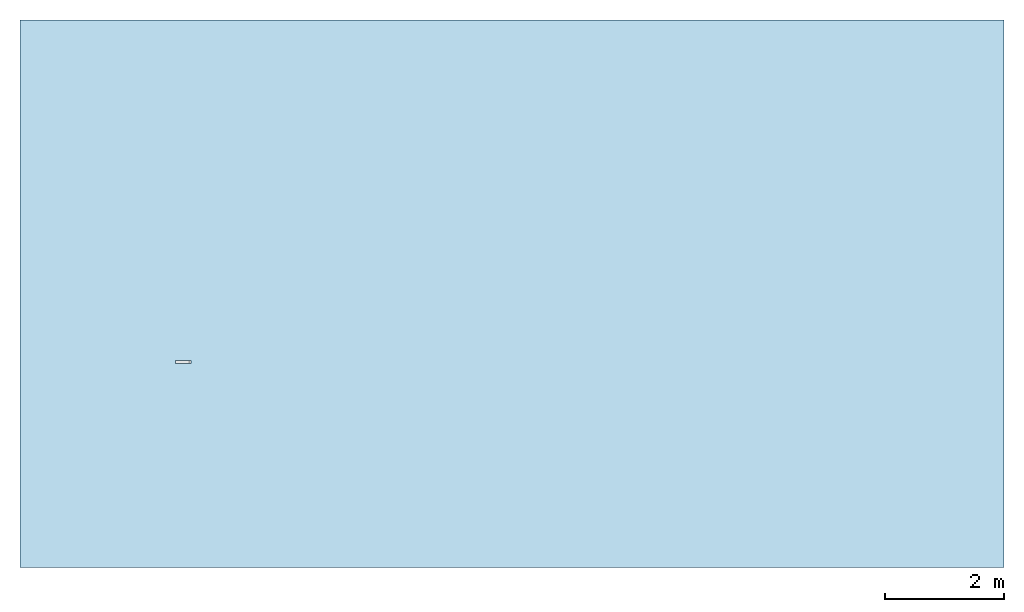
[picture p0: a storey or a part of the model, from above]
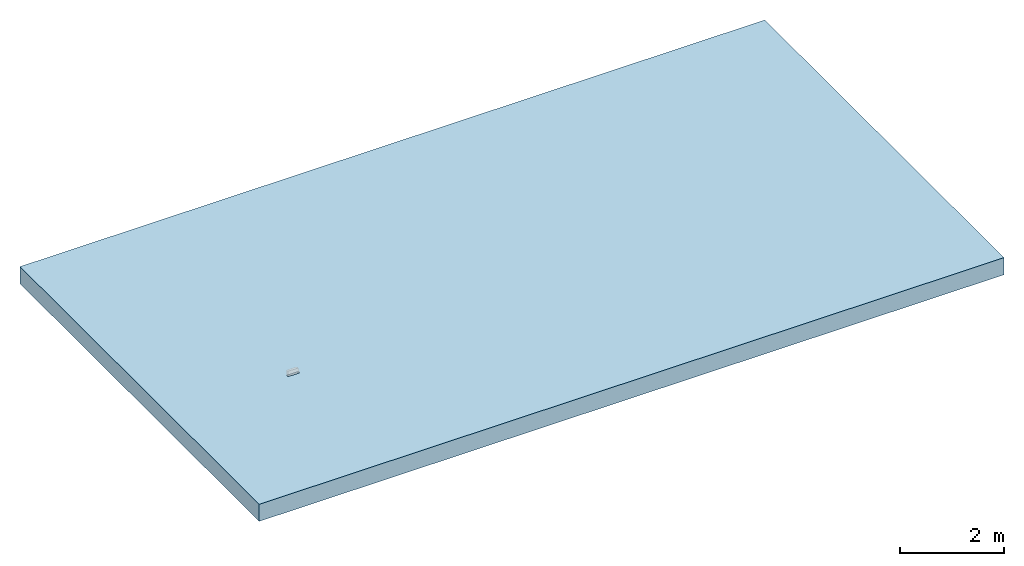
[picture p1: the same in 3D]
Properties of the parts of a building model (IFC2X3)

# File
Description: ViewDefinition [CoordinationView]
File name: T0134 - Closing end cap.ifc
Time: 2013-09-04T09:03:45
Written by: Autodesk Revit 2013
Made in: 20120221_2030(x64)

# IfcProject, Project Number
LongName: Project Name; Phase: Project Status

# IfcSite, Default
RefLatitude: 42, 21, 30, 344238; RefLongitude: -71, -3, -35, -194702; RefElevation: 0 mm

# IfcBuilding
Pset_BuildingCommon - NumberOfStoreys: 1
Other - Project Number: Project Number; Project Name: Project Name; Project Issue Date: Issue Date; Project Address: ## Street City, State Zip; Client Name: Owner; Project Status: Project Status

# IfcBuildingStorey, Level 1
LongName: Level 1; Elevation: 0 mm
Constraints - Elevation Base: 0; Elevation: 0 mm
Graphics - Line Pattern: Center; Line Weight: 1; Symbol at End 2 Default: yes; Color: 0; Symbol at End 1 Default: no; Symbol: M_Level Head - Circle: M_Level Head - Circle
Identity Data - Name: Level 1; Structural: no; Building Story: yes
Dimensions - Computation Height: 0 mm

# IfcBuildingElementProxy: T0134 - Closing end cap, Civil-Drainage-Channel-ACO-KerbDrain-KD200:T0134 - Closing end cap:T0134 - Closing end cap:308203
In: Level 1
Material: ACO Polymer Concrete.
Phasing - Phase Created: New Construction
Constraints - Level: Level: Level 1; Moves With Nearby Elements: no
Dimensions - Volume: 2985972 mm3; Void Depth.: -110 mm; Void length: 50 mm
Pset_BuildingElementProxyCommon - Reference: T0134 - Closing end cap
Identity Data - Assembly Description: Rain Water Drainage; Maintenance guidelines: http://www.aco.co.uk/download.php?id=120; e-mail Technical: technical@aco.co.uk; Assembly Code: D2040; URL: www.aco.co.uk; Type Comments: ACO KerbDrain KD200 half batter closing end cap; OmniClass Title: Rainwater Removal; Price: POA - contact ACO; Installation guidelines: http://www.aco.co.uk/download.php?id=120; Cost: 0; Manufacturer: ACO Technologies plc - ACO Water Management Division; Model: ACO KerbDrain KD200; Product Page URL: http://www.aco.co.uk/product_detail.php?id=3; Fax: +44 (0)1462 815895; Address: ACO Business Park, Hitchin Road, Shefford, Bedfordshire, United Kingdom SG17 5TE; OmniClass Number: 23.70.50.24; Product brochure: http://www.aco.co.uk/download.php?id=120; Model Description: Combined kerb and drainage system; Product Code: T0134; e-mail Sales: customersupport@aco.co.uk; Telephone: +44 (0)1462 816666
Data - Drainage Slot Width: N/A; Drainage Slot Intake area: N/A; Invert Depth: N/A; Installation - Concrete Grade: N/A; ACO Hydraulic Design Software: N/A; Concrete Surround Volume - Load Class A 15 - D 400 - Concrete Pavement: N/A; Product Standard: N/A; Product Dimensions: 50mm x 260mm x 235mm (LxWxH); Channel C.S.A: N/A; Load Class: N/A; Hydraulic Performance: N/A; Product Weight: 6.5 Kg
Construction - Channelunit_220: no; Blindunit_220: no; Access Cover: no; Blindunit_235: no; Channelunit_235: no; Closing end cap: yes; Accessunit_220: no; Accessunit_235: no
General - TagNumber: 0.000000; SerialNumber: 0.000000
Green Building Properties - Access Cover/Frame Recyclable: N/A; End Cap Recycled Material Content: 20% minimum; Access Cover/Frame Recycled Material Content: N/A; Channel Recycled Material Content: N/A; End Cap Recyclable: Fully recyclable; Channel Recyclable: N/A
Other - Revision: 1; CreatedBy: www.aco.co.uk
Materials and Finishes - Access Cover/Frame Colour: N/A; End Cap Colour: Grey; Access Cover/Frame Finish: N/A; Channel Colour: N/A; Channel Material: N/A; Access Cover/Frame Material: N/A; End Cap Material: Vienite® Synthetic Resin Concrete

# IfcOpeningElement: Recess
In: Level 1
Structural - Structural: no; Enable Analytical Model: no
Constraints - Level: Level: Level 1; Height Offset From Level: 0 mm; Related to Mass: no; Room Bounding: yes
Phasing - Phase Created: New Construction
Dimensions - Perimeter: 51360 mm; Thickness: 400 mm; Volume: 60586570000 mm3; Area: 151470000 mm2
Graphics - Coarse Scale Fill Color: 0
Analytical Properties - Roughness: 1; Absorptance: 0.1
Materials and Finishes - Structural Material: Plant
Construction - Function: 0; Default Thickness: 400 mm

# IfcSlab: Floor:Generic Floor - 400mm, Floor:Generic Floor - 400mm:193825
In: Level 1
PredefinedType: FLOOR; Material: Plant 400 mm
Structural - Structural: no; Enable Analytical Model: no
Constraints - Level: Level: Level 1; Height Offset From Level: 0 mm; Related to Mass: no; Room Bounding: yes
Phasing - Phase Created: New Construction
Dimensions - Perimeter: 51360 mm; Thickness: 400 mm; Volume: 60586570000 mm3; Area: 151470000 mm2
Pset_SlabCommon - Reference: Generic Floor - 400mm; IsExternal: no; LoadBearing: yes
Graphics - Coarse Scale Fill Color: 0
Analytical Properties - Roughness: 1; Absorptance: 0.1
Materials and Finishes - Structural Material: Plant
Construction - Function: 0; Default Thickness: 400 mm
